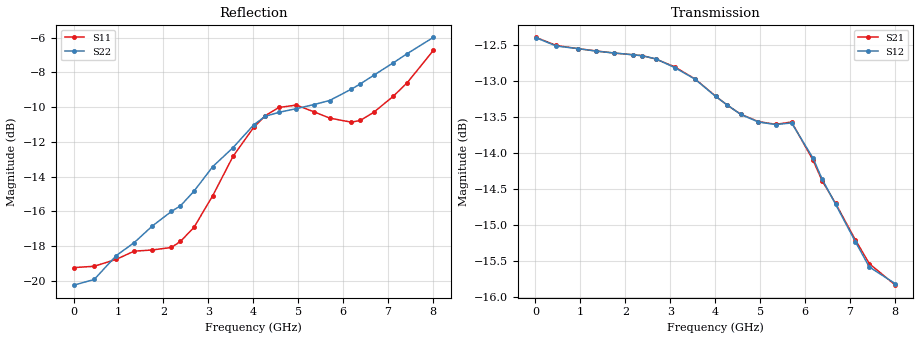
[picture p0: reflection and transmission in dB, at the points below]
! Device ID: PE43205
! Dir: z:\David_A\43205\PE43701\25C\3p300V\0p50dB
! Serial: 10
! Insertion: A
! Impedance: 50 ohm
! Temp: 25C
! VDD: 3.300V
! Attenuation Step: 0.50dB
! IDD: 1.237387e-01mA
#  Hz  S  RI  R  50
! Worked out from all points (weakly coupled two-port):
!   801 points, 10 MHz to 8.01 GHz, reference 50 ohm
!   highest |S21| = -12.40 dB at 10 MHz (marker M1); lowest = -15.8 dB at 8.01 GHz (marker M2)
!   lowest |S11| = -19.2 dB at 10 MHz (marker M3), VSWR 1.25, Z = 40.2 - j0.0477 ohm
!   |S11| at or under -10 dB: start of sweep to 4.578 GHz; 5.125 GHz to 6.861 GHz (1.736 GHz wide, 29 % of centre)
!   |S22| runs from -20.2 to -6.0 dB; largest |S21 - S12| = 0.0017
!   S11 on the Smith chart (normalised r, x): 10 MHz: 0.80, -0.00; 4.57 GHz: 0.52, +0.06; 7.12 GHz: 0.55, +0.30; 8.01 GHz: 0.41, +0.31
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1e7  -0.1093 -0.000587  0.24 -0.000994  0.2399 -0.00116  -0.0973 -0.00141
4.6e8  -0.1102 -0.00282  0.2362 -0.0186  0.236 -0.0183  -0.101 0.00216
9.5e8  -0.115 -0.00989  0.2329 -0.0363  0.2329 -0.0364  -0.1182 -0.00462
1.35e9  -0.1207 -0.0168  0.2293 -0.0508  0.2292 -0.0509  -0.1285 -0.0107
1.75e9  -0.1213 -0.0192  0.2248 -0.0652  0.2248 -0.0653  -0.1434 -0.0104
2.18e9  -0.1247 -0.00701  0.2191 -0.0805  0.2191 -0.0805  -0.1584 -0.00804
2.38e9  -0.13 0.00119  0.216 -0.0876  0.2159 -0.0877  -0.1645 -0.00183
2.68e9  -0.1416 0.0168  0.2101 -0.098  0.2101 -0.0982  -0.1809 0.00992
3.1e9  -0.171 0.0422  0.1999 -0.1116  0.1996 -0.1116  -0.2122 0.0227
3.55e9  -0.2192 0.0639  0.1868 -0.1247  0.1867 -0.1247  -0.2392 0.0363
4.01e9  -0.2681 0.0685  0.1724 -0.1342  0.1723 -0.1342  -0.276 0.0541
4.27e9  -0.2927 0.0617  0.1654 -0.1379  0.1654 -0.138  -0.293 0.0536
4.57e9  -0.3114 0.0516  0.1575 -0.1423  0.1575 -0.1422  -0.3003 0.0567
4.96e9  -0.3183 0.0397  0.1487 -0.148  0.1486 -0.1479  -0.3038 0.0764
5.35e9  -0.3033 0.0461  0.1391 -0.1558  0.1391 -0.1557  -0.3026 0.1095
5.7e9  -0.2857 0.0707  0.1282 -0.1659  0.1278 -0.1658  -0.2974 0.1444
6.18e9  -0.2531 0.1341  0.1042 -0.1674  0.1046 -0.1679  -0.29 0.2068
6.38e9  -0.2388 0.1639  0.0949 -0.1656  0.0954 -0.1659  -0.2861 0.2327
6.68e9  -0.2291 0.2023  0.0859 -0.1628  0.0863 -0.1623  -0.2844 0.2678
7.12e9  -0.239 0.2422  0.0742 -0.157  0.0739 -0.1566  -0.2784 0.3206
7.43e9  -0.2704 0.2559  0.0707 -0.1515  0.0701 -0.1508  -0.2804 0.3535
8.01e9  -0.3513 0.2981  0.0683 -0.1464  0.067 -0.1474  -0.2898 0.4102
